(* Logix 5000 AddOnInstructionDefinition export UpdateSignVariables; software revision 17.00; part 2 of 2 *)
(* tags used below, declared in another part *)
   ENVariable3Update : BOOL;   // 0 = don't update this variable 1 = update this variable
   ENVariable4Update : BOOL;   // 0 = don't update this variable 1 = update this variable
   DN : BOOL;   // Instruction Interface Done Bit
   ER : BOOL;   // Instruction Interface Error Bit
   map_SignOutput : SINT[496];   // Ethernet/IP LEDSIGN.O Data I/O Mapping
   Packet1Sent : STRING;   // The actual packet sent to the sign (Packet1)
   Packet2Sent : STRING;   // The actual packet sent to the sign (Packet2)
   Packet3Sent : STRING;   // The actual packet sent to the sign (Packet3)
   SEQ : DINT;   // Sequence Number
   InCycle : BOOL;   // Incycle
   Error : BOOL;   // Error
   Done : BOOL;   // Done
   SignETX : STRING;   // DO NOT EDIT = ^C
   SignSOH : STRING;   // DO NOT EDIT = ^A
   SignAddress : STRING;
   SignSTX : STRING;   // DO NOT EDIT = ^B
   SignVariable4Name : STRING;
   SignCommandCode : STRING;   // DO NOT EDIT = B
   SignVariable4Value : STRING;
   TotalPacketCount : DINT[7];   // Total Character Count
   Select : DINT;   // Packet Array Select
   PacketMax : DINT;   // Max Packet Count
   Packet3Offset : DINT;
   Packet2Offset : DINT;
   Packet1Offset : DINT;
   Packet : STRING[7];   // Packet Array to send to sign
(* UpdateSignVariables, continued *)

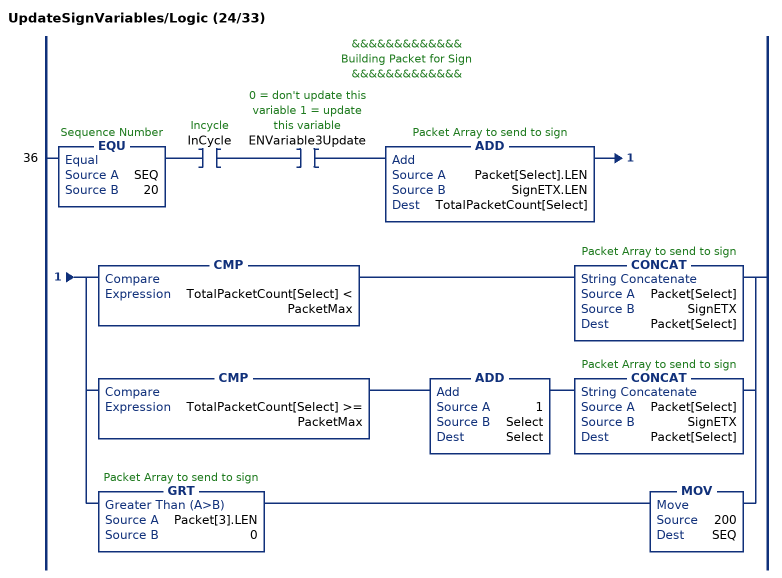
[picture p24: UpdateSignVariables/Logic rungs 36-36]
   // &&&&&&&&&&&&&
   // Building Packet for Sign
   // &&&&&&&&&&&&&
   36: EQU(SEQ,20)XIC(InCycle)XIC(ENVariable3Update)ADD(Packet[Select].LEN,SignETX.LEN,TotalPacketCount[Select])[CMP(TotalPacketCount[Select] < PacketMax) CONCAT(Packet[Select],SignETX,Packet[Select]) ,CMP(TotalPacketCount[Select] >= PacketMax) ADD(1,Select,Select) CONCAT(Packet[Select],SignETX,Packet[Select]) ,GRT(Packet[3].LEN,0) MOV(200,SEQ) ];
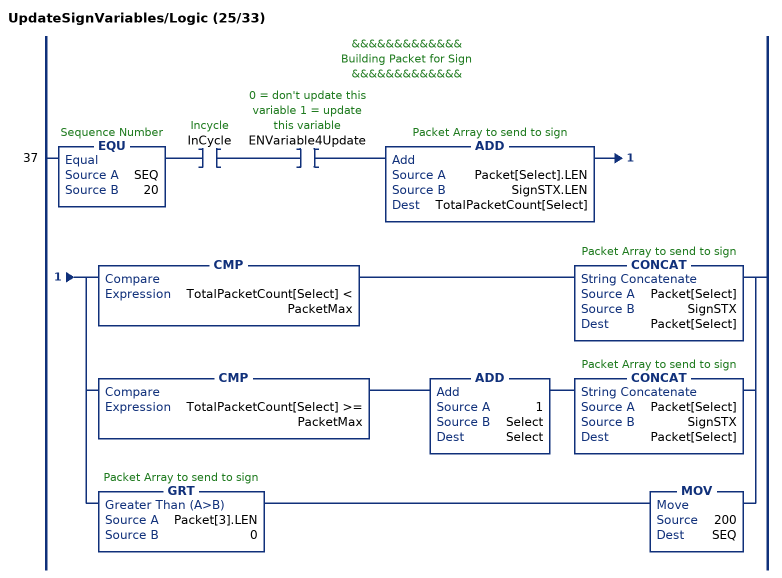
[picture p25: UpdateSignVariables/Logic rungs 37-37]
   // &&&&&&&&&&&&&
   // Building Packet for Sign
   // &&&&&&&&&&&&&
   37: EQU(SEQ,20)XIC(InCycle)XIC(ENVariable4Update)ADD(Packet[Select].LEN,SignSTX.LEN,TotalPacketCount[Select])[CMP(TotalPacketCount[Select] < PacketMax) CONCAT(Packet[Select],SignSTX,Packet[Select]) ,CMP(TotalPacketCount[Select] >= PacketMax) ADD(1,Select,Select) CONCAT(Packet[Select],SignSTX,Packet[Select]) ,GRT(Packet[3].LEN,0) MOV(200,SEQ) ];
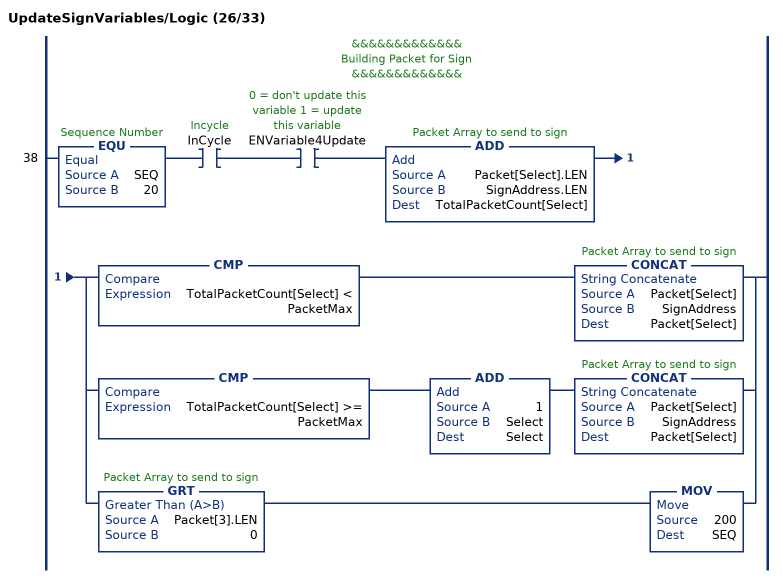
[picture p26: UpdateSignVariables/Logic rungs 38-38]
   // &&&&&&&&&&&&&
   // Building Packet for Sign
   // &&&&&&&&&&&&&
   38: EQU(SEQ,20)XIC(InCycle)XIC(ENVariable4Update)ADD(Packet[Select].LEN,SignAddress.LEN,TotalPacketCount[Select])[CMP(TotalPacketCount[Select] < PacketMax) CONCAT(Packet[Select],SignAddress,Packet[Select]) ,CMP(TotalPacketCount[Select] >= PacketMax) ADD(1,Select,Select) CONCAT(Packet[Select],SignAddress,Packet[Select]) ,GRT(Packet[3].LEN,0) MOV(200,SEQ) ];
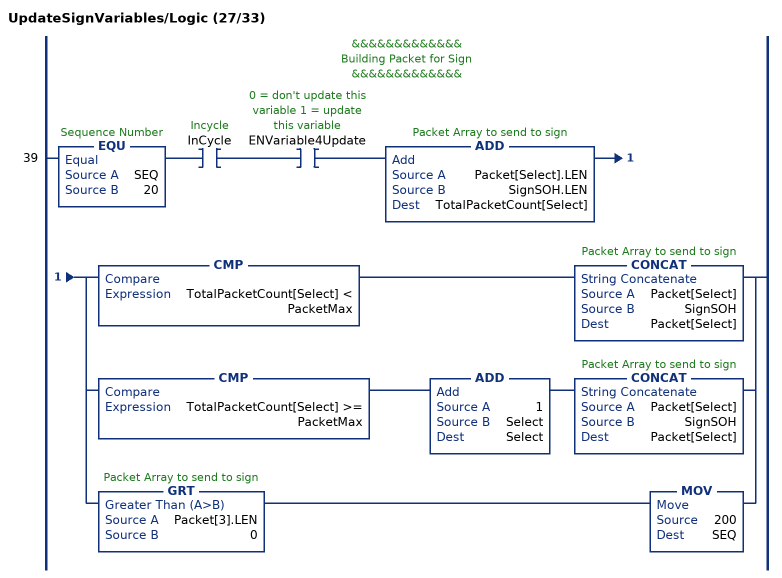
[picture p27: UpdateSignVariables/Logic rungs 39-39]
   // &&&&&&&&&&&&&
   // Building Packet for Sign
   // &&&&&&&&&&&&&
   39: EQU(SEQ,20)XIC(InCycle)XIC(ENVariable4Update)ADD(Packet[Select].LEN,SignSOH.LEN,TotalPacketCount[Select])[CMP(TotalPacketCount[Select] < PacketMax) CONCAT(Packet[Select],SignSOH,Packet[Select]) ,CMP(TotalPacketCount[Select] >= PacketMax) ADD(1,Select,Select) CONCAT(Packet[Select],SignSOH,Packet[Select]) ,GRT(Packet[3].LEN,0) MOV(200,SEQ) ];
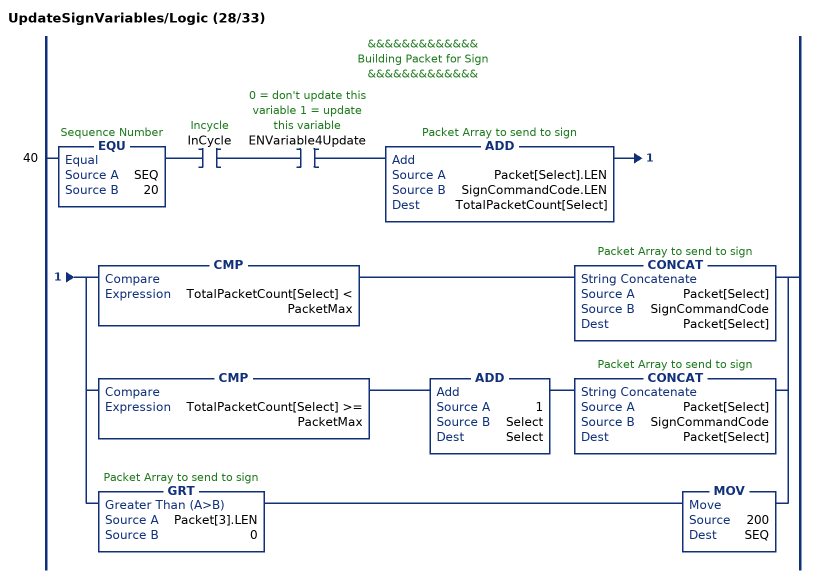
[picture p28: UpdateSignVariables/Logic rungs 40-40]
   // &&&&&&&&&&&&&
   // Building Packet for Sign
   // &&&&&&&&&&&&&
   40: EQU(SEQ,20)XIC(InCycle)XIC(ENVariable4Update)ADD(Packet[Select].LEN,SignCommandCode.LEN,TotalPacketCount[Select])[CMP(TotalPacketCount[Select] < PacketMax) CONCAT(Packet[Select],SignCommandCode,Packet[Select]) ,CMP(TotalPacketCount[Select] >= PacketMax) ADD(1,Select,Select) CONCAT(Packet[Select],SignCommandCode,Packet[Select]) ,GRT(Packet[3].LEN,0) MOV(200,SEQ) ];
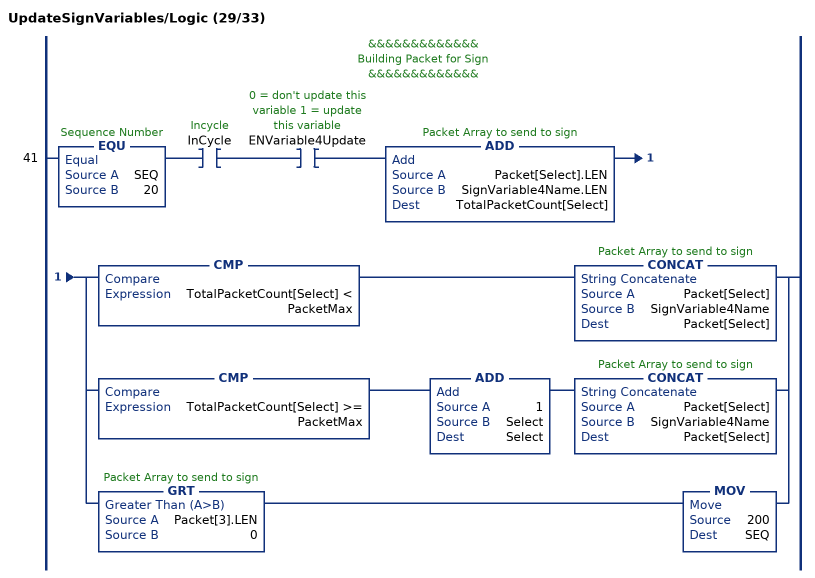
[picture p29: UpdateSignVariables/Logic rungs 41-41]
   // &&&&&&&&&&&&&
   // Building Packet for Sign
   // &&&&&&&&&&&&&
   41: EQU(SEQ,20)XIC(InCycle)XIC(ENVariable4Update)ADD(Packet[Select].LEN,SignVariable4Name.LEN,TotalPacketCount[Select])[CMP(TotalPacketCount[Select] < PacketMax) CONCAT(Packet[Select],SignVariable4Name,Packet[Select]) ,CMP(TotalPacketCount[Select] >= PacketMax) ADD(1,Select,Select) CONCAT(Packet[Select],SignVariable4Name,Packet[Select]) ,GRT(Packet[3].LEN,0) MOV(200,SEQ) ];
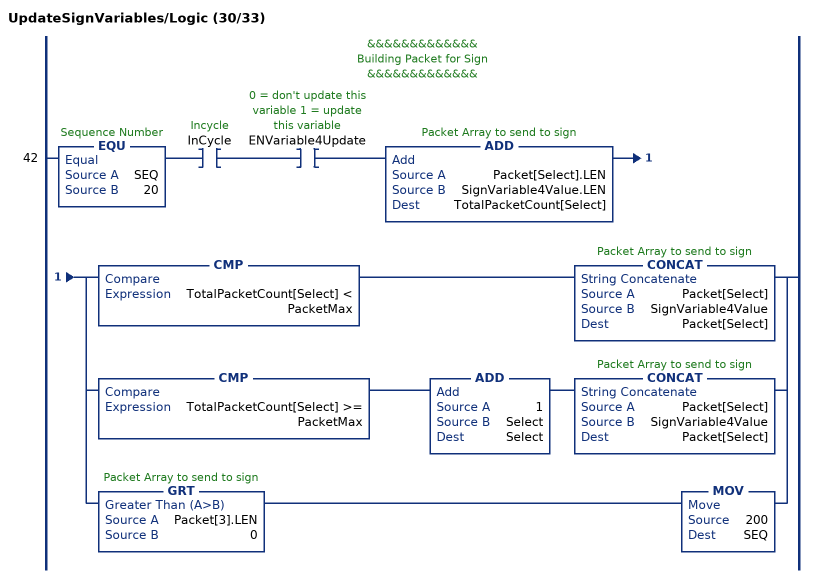
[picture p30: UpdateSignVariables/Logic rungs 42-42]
   // &&&&&&&&&&&&&
   // Building Packet for Sign
   // &&&&&&&&&&&&&
   42: EQU(SEQ,20)XIC(InCycle)XIC(ENVariable4Update)ADD(Packet[Select].LEN,SignVariable4Value.LEN,TotalPacketCount[Select])[CMP(TotalPacketCount[Select] < PacketMax) CONCAT(Packet[Select],SignVariable4Value,Packet[Select]) ,CMP(TotalPacketCount[Select] >= PacketMax) ADD(1,Select,Select) CONCAT(Packet[Select],SignVariable4Value,Packet[Select]) ,GRT(Packet[3].LEN,0) MOV(200,SEQ) ];
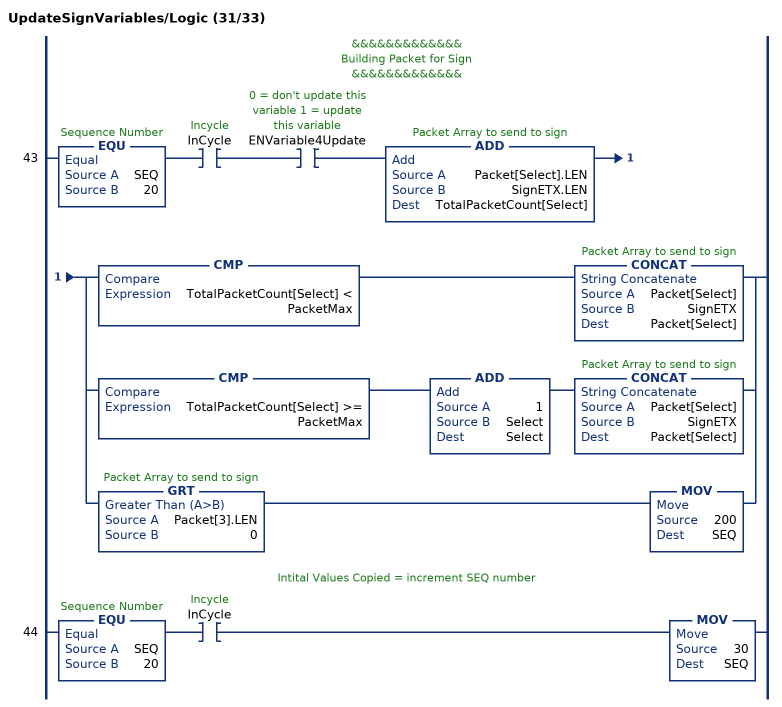
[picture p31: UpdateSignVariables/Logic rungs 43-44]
   // &&&&&&&&&&&&&
   // Building Packet for Sign
   // &&&&&&&&&&&&&
   43: EQU(SEQ,20)XIC(InCycle)XIC(ENVariable4Update)ADD(Packet[Select].LEN,SignETX.LEN,TotalPacketCount[Select])[CMP(TotalPacketCount[Select] < PacketMax) CONCAT(Packet[Select],SignETX,Packet[Select]) ,CMP(TotalPacketCount[Select] >= PacketMax) ADD(1,Select,Select) CONCAT(Packet[Select],SignETX,Packet[Select]) ,GRT(Packet[3].LEN,0) MOV(200,SEQ) ];
   // Intital Values Copied = increment SEQ number
   44: EQU(SEQ,20)XIC(InCycle)MOV(30,SEQ);
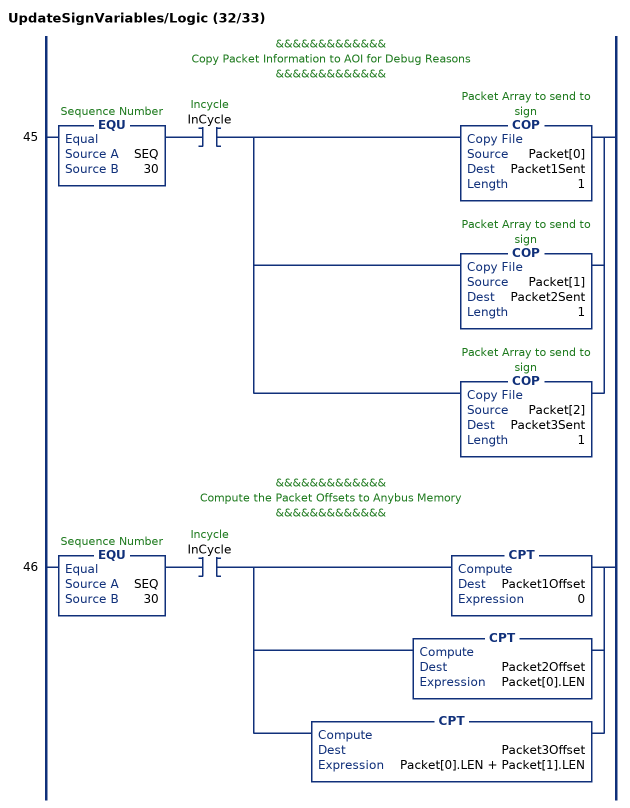
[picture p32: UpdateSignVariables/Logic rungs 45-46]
   // &&&&&&&&&&&&&
   // Copy Packet Information to AOI for Debug Reasons
   // &&&&&&&&&&&&&
   45: EQU(SEQ,30)XIC(InCycle)[COP(Packet[0],Packet1Sent,1) ,COP(Packet[1],Packet2Sent,1) ,COP(Packet[2],Packet3Sent,1) ];
   // &&&&&&&&&&&&&
   // Compute the Packet Offsets to Anybus Memory
   // &&&&&&&&&&&&&
   46: EQU(SEQ,30)XIC(InCycle)[CPT(Packet1Offset,0) ,CPT(Packet2Offset,Packet[0].LEN) ,CPT(Packet3Offset,Packet[0].LEN + Packet[1].LEN) ];
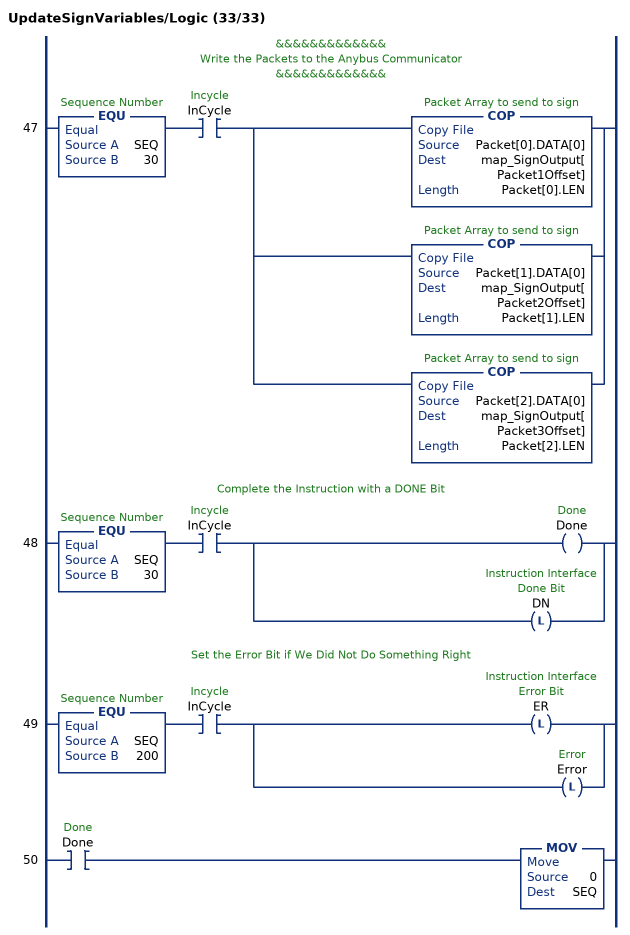
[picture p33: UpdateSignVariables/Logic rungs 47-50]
   // &&&&&&&&&&&&&
   // Write the Packets to the Anybus Communicator
   // &&&&&&&&&&&&&
   47: EQU(SEQ,30)XIC(InCycle)[COP(Packet[0].DATA[0],map_SignOutput[Packet1Offset],Packet[0].LEN) ,COP(Packet[1].DATA[0],map_SignOutput[Packet2Offset],Packet[1].LEN) ,COP(Packet[2].DATA[0],map_SignOutput[Packet3Offset],Packet[2].LEN) ];
   // Complete the Instruction with a DONE Bit
   48: EQU(SEQ,30)XIC(InCycle)[OTE(Done) ,OTL(DN) ];
   // Set the Error Bit if We Did Not Do Something Right
   49: EQU(SEQ,200)XIC(InCycle)[OTL(ER) ,OTL(Error) ];
   50: XIC(Done)MOV(0,SEQ);
END_ROUTINE
END_ADD_ON_INSTRUCTION
